VERSION 5.8 ;
BUSBITCHARS "[]" ;
DIVIDERCHAR "/" ;
UNITS
    DATABASE MICRONS 1000 ;
END UNITS

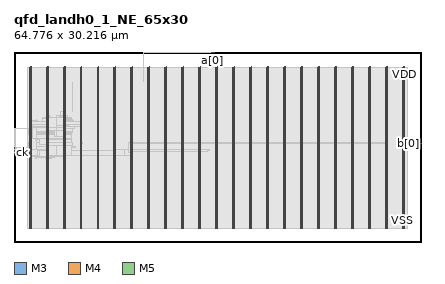
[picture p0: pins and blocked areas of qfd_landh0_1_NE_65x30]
MACRO qfd_landh0_1_NE_65x30
  FOREIGN qfd_landh0_1_NE_65x30 0 0 ;
  CLASS BLOCK ;
  SIZE 64.776 BY 30.216 ;
  PIN a[0]
    DIRECTION INPUT ;
    USE SIGNAL ;
    PORT
      LAYER M3 ;
        RECT  31.86 30.179 31.878 30.216 ;
    END
    PORT
      LAYER M3 ;
        RECT  31.356 30.109 31.878 30.204 ;
    END
  END a[0]
  PIN b[0]
    DIRECTION OUTPUT ;
    USE SIGNAL ;
    PORT
      LAYER M4 ;
        RECT  64.692 15.6 64.776 15.624 ;
    END
    PORT
      LAYER M4 ;
        RECT  63.853 15.6 64.716 15.624 ;
    END
  END b[0]
  PIN ck
    DIRECTION INPUT ;
    USE SIGNAL ;
    PORT
      LAYER M4 ;
        RECT  0 14.16 0.084 14.184 ;
    END
  END ck
  PIN ck_s
    DIRECTION INPUT ;
    USE SIGNAL ;
    PORT
      LAYER M4 ;
        RECT  0 14.256 0.084 14.28 ;
    END
  END ck_s
  PIN en
    DIRECTION INPUT ;
    USE SIGNAL ;
    PORT
      LAYER M4 ;
        RECT  0 14.352 0.084 14.376 ;
    END
  END en
  PIN fault
    DIRECTION OUTPUT ;
    USE SIGNAL ;
    PORT
      LAYER M4 ;
        RECT  0 14.448 0.084 14.472 ;
    END
  END fault
  PIN k0
    DIRECTION INPUT ;
    USE SIGNAL ;
    PORT
      LAYER M4 ;
        RECT  0 14.544 0.084 14.568 ;
    END
  END k0
  PIN k1
    DIRECTION INPUT ;
    USE SIGNAL ;
    PORT
      LAYER M4 ;
        RECT  0 14.64 0.084 14.664 ;
    END
  END k1
  PIN k2
    DIRECTION INPUT ;
    USE SIGNAL ;
    PORT
      LAYER M4 ;
        RECT  0 14.736 0.084 14.76 ;
    END
  END k2
  PIN rs
    DIRECTION INPUT ;
    USE SIGNAL ;
    PORT
      LAYER M4 ;
        RECT  0 14.832 0.084 14.856 ;
    END
  END rs
  PIN tie_hi
    DIRECTION OUTPUT ;
    USE SIGNAL ;
    PORT
      LAYER M4 ;
        RECT  0 14.928 0.084 14.952 ;
    END
  END tie_hi
  PIN tie_lo
    DIRECTION OUTPUT ;
    USE SIGNAL ;
    PORT
      LAYER M4 ;
        RECT  0 15.024 0.084 15.048 ;
    END
  END tie_lo
  PIN VDD
    DIRECTION INOUT ;
    USE POWER ;
    PORT
      LAYER M5 ;
        RECT  61.992 2.151 62.112 27.833 ;
        RECT  59.292 2.151 59.412 27.833 ;
        RECT  56.592 2.151 56.712 27.833 ;
        RECT  53.892 2.151 54.012 27.833 ;
        RECT  51.192 2.151 51.312 27.833 ;
        RECT  48.492 2.151 48.612 27.833 ;
        RECT  45.792 2.151 45.912 27.833 ;
        RECT  43.092 2.151 43.212 27.833 ;
        RECT  40.392 2.151 40.512 27.833 ;
        RECT  37.692 2.151 37.812 27.833 ;
        RECT  34.992 2.151 35.112 27.833 ;
        RECT  32.292 2.151 32.412 27.833 ;
        RECT  29.592 2.151 29.712 27.833 ;
        RECT  26.892 2.151 27.012 27.833 ;
        RECT  24.192 2.151 24.312 27.833 ;
        RECT  21.492 2.151 21.612 27.833 ;
        RECT  18.792 2.151 18.912 27.833 ;
        RECT  16.092 2.151 16.212 27.833 ;
        RECT  13.392 2.151 13.512 27.833 ;
        RECT  10.692 2.151 10.812 27.833 ;
        RECT  7.992 2.151 8.112 27.833 ;
        RECT  5.292 2.151 5.412 27.833 ;
        RECT  2.592 2.151 2.712 27.833 ;
    END
  END VDD
  PIN VSS
    DIRECTION INOUT ;
    USE GROUND ;
    PORT
      LAYER M5 ;
        RECT  61.8 2.137 61.92 27.819 ;
        RECT  59.1 2.137 59.22 27.819 ;
        RECT  56.4 2.137 56.52 27.819 ;
        RECT  53.7 2.137 53.82 27.819 ;
        RECT  51 2.137 51.12 27.819 ;
        RECT  48.3 2.137 48.42 27.819 ;
        RECT  45.6 2.137 45.72 27.819 ;
        RECT  42.9 2.137 43.02 27.819 ;
        RECT  40.2 2.137 40.32 27.819 ;
        RECT  37.5 2.137 37.62 27.819 ;
        RECT  34.8 2.137 34.92 27.819 ;
        RECT  32.1 2.137 32.22 27.819 ;
        RECT  29.4 2.137 29.52 27.819 ;
        RECT  26.7 2.137 26.82 27.819 ;
        RECT  24 2.137 24.12 27.819 ;
        RECT  21.3 2.137 21.42 27.819 ;
        RECT  18.6 2.137 18.72 27.819 ;
        RECT  15.9 2.137 16.02 27.819 ;
        RECT  13.2 2.137 13.32 27.819 ;
        RECT  10.5 2.137 10.62 27.819 ;
        RECT  7.8 2.137 7.92 27.819 ;
        RECT  5.1 2.137 5.22 27.819 ;
        RECT  2.4 2.137 2.52 27.819 ;
    END
  END VSS
  # OT_OBS_CLOSED layer=M5 d_um=1.536 added=3
  OBS
    LAYER RVTN ;
     RECT  2.16 2.16 62.586 2.295 ;
     RECT  2.16 2.565 62.586 2.835 ;
     RECT  2.16 3.105 62.586 3.375 ;
     RECT  2.16 3.645 62.586 3.915 ;
     RECT  2.16 4.185 62.586 4.455 ;
     RECT  2.16 4.725 62.586 4.995 ;
     RECT  2.16 5.265 62.586 5.535 ;
     RECT  2.16 5.805 62.586 6.075 ;
     RECT  2.16 6.345 62.586 6.615 ;
     RECT  2.16 6.885 62.586 7.155 ;
     RECT  2.16 7.425 62.586 7.695 ;
     RECT  2.16 7.965 62.586 8.235 ;
     RECT  2.16 8.505 62.586 8.775 ;
     RECT  2.16 9.045 62.586 9.315 ;
     RECT  2.16 9.585 62.586 9.855 ;
     RECT  2.16 10.125 62.586 10.395 ;
     RECT  2.16 10.665 62.586 10.935 ;
     RECT  2.16 11.205 62.586 11.475 ;
     RECT  2.16 11.745 62.586 12.015 ;
     RECT  2.16 12.285 62.586 12.555 ;
     RECT  2.16 12.825 62.586 13.095 ;
     RECT  2.16 13.365 62.586 13.635 ;
     RECT  2.16 13.905 62.586 14.175 ;
     RECT  2.16 14.445 62.586 14.715 ;
     RECT  2.16 14.985 62.586 15.255 ;
     RECT  2.16 15.525 62.586 15.795 ;
     RECT  2.16 16.065 62.586 16.335 ;
     RECT  2.16 16.605 62.586 16.875 ;
     RECT  2.16 17.145 62.586 17.415 ;
     RECT  2.16 17.685 62.586 17.955 ;
     RECT  2.16 18.225 62.586 18.495 ;
     RECT  2.16 18.765 62.586 19.035 ;
     RECT  2.16 19.305 62.586 19.575 ;
     RECT  2.16 19.845 62.586 20.115 ;
     RECT  2.16 20.385 62.586 20.655 ;
     RECT  2.16 20.925 62.586 21.195 ;
     RECT  2.16 21.465 62.586 21.735 ;
     RECT  2.16 22.005 62.586 22.275 ;
     RECT  2.16 22.545 62.586 22.815 ;
     RECT  2.16 23.085 62.586 23.355 ;
     RECT  2.16 23.625 62.586 23.895 ;
     RECT  2.16 24.165 62.586 24.435 ;
     RECT  2.16 24.705 62.586 24.975 ;
     RECT  2.16 25.245 62.586 25.515 ;
     RECT  2.16 25.785 62.586 26.055 ;
     RECT  2.16 26.325 62.586 26.595 ;
     RECT  2.16 26.865 62.586 27.135 ;
     RECT  2.16 27.405 62.586 27.675 ;
    LAYER RVTP ;
     RECT  2.16 2.295 62.586 2.565 ;
     RECT  2.16 2.835 62.586 3.105 ;
     RECT  2.16 3.375 62.586 3.645 ;
     RECT  2.16 3.915 62.586 4.185 ;
     RECT  2.16 4.455 62.586 4.725 ;
     RECT  2.16 4.995 62.586 5.265 ;
     RECT  2.16 5.535 62.586 5.805 ;
     RECT  2.16 6.075 62.586 6.345 ;
     RECT  2.16 6.615 62.586 6.885 ;
     RECT  2.16 7.155 62.586 7.425 ;
     RECT  2.16 7.695 62.586 7.965 ;
     RECT  2.16 8.235 62.586 8.505 ;
     RECT  2.16 8.775 62.586 9.045 ;
     RECT  2.16 9.315 62.586 9.585 ;
     RECT  2.16 9.855 62.586 10.125 ;
     RECT  2.16 10.395 62.586 10.665 ;
     RECT  2.16 10.935 62.586 11.205 ;
     RECT  2.16 11.475 62.586 11.745 ;
     RECT  2.16 12.015 62.586 12.285 ;
     RECT  2.16 12.555 62.586 12.825 ;
     RECT  2.16 13.095 62.586 13.365 ;
     RECT  2.16 13.635 62.586 13.905 ;
     RECT  2.16 14.175 62.586 14.445 ;
     RECT  2.16 14.715 62.586 14.985 ;
     RECT  2.16 15.255 62.586 15.525 ;
     RECT  2.16 15.795 62.586 16.065 ;
     RECT  2.16 16.335 62.586 16.605 ;
     RECT  2.16 16.875 62.586 17.145 ;
     RECT  2.16 17.415 62.586 17.685 ;
     RECT  2.16 17.955 62.586 18.225 ;
     RECT  2.16 18.495 62.586 18.765 ;
     RECT  2.16 19.035 62.586 19.305 ;
     RECT  2.16 19.575 62.586 19.845 ;
     RECT  2.16 20.115 62.586 20.385 ;
     RECT  2.16 20.655 62.586 20.925 ;
     RECT  2.16 21.195 62.586 21.465 ;
     RECT  2.16 21.735 62.586 22.005 ;
     RECT  2.16 22.275 62.586 22.545 ;
     RECT  2.16 22.815 62.586 23.085 ;
     RECT  2.16 23.355 62.586 23.625 ;
     RECT  2.16 23.895 62.586 24.165 ;
     RECT  2.16 24.435 62.586 24.705 ;
     RECT  2.16 24.975 62.586 25.245 ;
     RECT  2.16 25.515 62.586 25.785 ;
     RECT  2.16 26.055 62.586 26.325 ;
     RECT  2.16 26.595 62.586 26.865 ;
     RECT  2.16 27.135 62.586 27.405 ;
     RECT  2.16 27.675 62.586 27.81 ;
    LAYER M1 ;
     RECT  2.16 2.151 62.586 27.819 ;
    LAYER M2 ;
     RECT  0.103 14.454 0.455 14.742 ;
     RECT  20.551 30.186 31.351 30.204 ;
     RECT  31.351 30.114 31.379 30.204 ;
     RECT  31.379 30.114 31.883 30.132 ;
     RECT  2.16 2.151 62.586 27.819 ;
     RECT  62.586 15.732 63.887 15.75 ;
    LAYER M3 ;
     RECT  2.415 2.143 2.505 2.413 ;
     RECT  5.115 2.143 5.205 2.413 ;
     RECT  7.815 2.143 7.905 2.413 ;
     RECT  10.515 2.143 10.605 2.413 ;
     RECT  13.215 2.143 13.305 2.413 ;
     RECT  15.915 2.143 16.005 2.413 ;
     RECT  18.615 2.143 18.705 2.413 ;
     RECT  21.315 2.143 21.405 2.413 ;
     RECT  24.015 2.143 24.105 2.413 ;
     RECT  26.715 2.143 26.805 2.413 ;
     RECT  29.415 2.143 29.505 2.413 ;
     RECT  32.115 2.143 32.205 2.413 ;
     RECT  34.815 2.143 34.905 2.413 ;
     RECT  37.515 2.143 37.605 2.413 ;
     RECT  40.215 2.143 40.305 2.413 ;
     RECT  42.915 2.143 43.005 2.413 ;
     RECT  45.615 2.143 45.705 2.413 ;
     RECT  48.315 2.143 48.405 2.413 ;
     RECT  51.015 2.143 51.105 2.413 ;
     RECT  53.715 2.143 53.805 2.413 ;
     RECT  56.415 2.143 56.505 2.413 ;
     RECT  59.115 2.143 59.205 2.413 ;
     RECT  61.815 2.143 61.905 2.413 ;
     RECT  5.115 2.413 5.397 13.297 ;
     RECT  5.115 13.297 5.922 13.333 ;
     RECT  4.32 13.333 4.338 13.369 ;
     RECT  5.076 13.333 6.03 13.369 ;
     RECT  3.492 13.261 3.51 13.405 ;
     RECT  4.32 13.369 6.03 13.405 ;
     RECT  3.492 13.405 6.03 13.441 ;
     RECT  2.415 2.413 2.697 13.531 ;
     RECT  3.492 13.441 6.426 13.531 ;
     RECT  7.815 2.413 8.097 13.531 ;
     RECT  2.415 13.531 6.426 13.667 ;
     RECT  6.228 13.667 6.426 13.675 ;
     RECT  7.236 13.531 8.097 13.675 ;
     RECT  18.615 2.413 18.897 13.819 ;
     RECT  2.415 13.667 5.49 14.143 ;
     RECT  18 13.819 18.897 14.215 ;
     RECT  17.532 14.215 18.897 14.237 ;
     RECT  2.376 14.143 5.49 14.347 ;
     RECT  15.915 2.413 16.197 14.347 ;
     RECT  0.144 14.299 0.162 14.44 ;
     RECT  0.108 14.44 0.162 14.449 ;
     RECT  30.744 14.443 30.762 14.611 ;
     RECT  17.532 14.237 17.658 14.635 ;
     RECT  30.744 14.611 31.086 14.639 ;
     RECT  15.876 14.347 16.197 14.669 ;
     RECT  2.304 14.347 5.49 14.675 ;
     RECT  17.424 14.635 17.658 14.675 ;
     RECT  17.532 14.675 17.55 14.717 ;
     RECT  31.068 14.639 31.086 14.717 ;
     RECT  0.108 14.449 0.45 14.747 ;
     RECT  0.144 14.747 0.45 14.765 ;
     RECT  2.304 14.675 2.826 14.765 ;
     RECT  6.228 13.675 8.097 15.061 ;
     RECT  9.036 15.025 9.702 15.061 ;
     RECT  6.228 15.061 9.702 15.179 ;
     RECT  3.636 14.675 5.49 15.259 ;
     RECT  6.228 15.179 9.27 15.259 ;
     RECT  10.515 2.413 10.797 15.691 ;
     RECT  59.115 2.413 59.397 15.727 ;
     RECT  61.815 2.413 62.097 15.727 ;
     RECT  2.304 14.765 2.697 15.755 ;
     RECT  3.636 15.259 9.27 15.755 ;
     RECT  63.864 15.595 63.882 15.755 ;
     RECT  59.112 15.727 59.397 15.773 ;
     RECT  10.515 15.691 10.854 15.899 ;
     RECT  61.56 15.727 62.097 15.899 ;
     RECT  3.636 15.755 9.162 16.339 ;
     RECT  3.456 16.339 9.162 16.411 ;
     RECT  2.415 15.755 2.697 16.459 ;
     RECT  3.42 16.411 9.162 16.459 ;
     RECT  2.415 16.459 9.162 17.083 ;
     RECT  2.376 17.083 9.162 17.221 ;
     RECT  2.376 17.221 9.198 17.491 ;
     RECT  2.376 17.491 9.234 17.609 ;
     RECT  2.415 17.609 9.234 18.031 ;
     RECT  2.415 18.031 9.594 18.301 ;
     RECT  10.515 15.899 10.797 18.301 ;
     RECT  2.415 18.301 10.797 18.689 ;
     RECT  2.415 18.689 5.397 19.229 ;
     RECT  6.12 18.689 10.797 19.229 ;
     RECT  6.12 19.229 9.522 19.265 ;
     RECT  2.415 19.229 3.726 19.301 ;
     RECT  3.528 19.301 3.726 19.373 ;
     RECT  6.12 19.265 9.306 19.499 ;
     RECT  3.528 19.373 3.546 19.535 ;
     RECT  4.5 19.229 5.397 19.579 ;
     RECT  6.12 19.499 9.162 19.579 ;
     RECT  4.5 19.579 9.162 19.769 ;
     RECT  4.644 19.769 8.586 19.841 ;
     RECT  5.115 19.841 8.586 19.877 ;
     RECT  5.115 19.877 5.85 19.949 ;
     RECT  6.732 19.877 8.586 20.039 ;
     RECT  5.115 19.949 5.67 20.075 ;
     RECT  6.732 20.039 8.406 20.075 ;
     RECT  7.38 20.075 8.19 20.687 ;
     RECT  9.252 20.695 9.27 25.439 ;
     RECT  2.415 19.301 2.697 27.557 ;
     RECT  5.115 20.075 5.397 27.557 ;
     RECT  7.815 20.687 8.097 27.557 ;
     RECT  10.515 19.229 10.797 27.557 ;
     RECT  13.215 2.413 13.497 27.557 ;
     RECT  15.915 14.669 16.197 27.557 ;
     RECT  18.615 14.237 18.897 27.557 ;
     RECT  21.315 2.413 21.597 27.557 ;
     RECT  24.015 2.413 24.297 27.557 ;
     RECT  26.715 2.413 26.997 27.557 ;
     RECT  29.415 2.413 29.697 27.557 ;
     RECT  32.115 2.413 32.397 27.557 ;
     RECT  34.815 2.413 35.097 27.557 ;
     RECT  37.515 2.413 37.797 27.557 ;
     RECT  40.215 2.413 40.497 27.557 ;
     RECT  42.915 2.413 43.197 27.557 ;
     RECT  45.615 2.413 45.897 27.557 ;
     RECT  48.315 2.413 48.597 27.557 ;
     RECT  51.015 2.413 51.297 27.557 ;
     RECT  53.715 2.413 53.997 27.557 ;
     RECT  56.415 2.413 56.697 27.557 ;
     RECT  59.115 15.773 59.397 27.557 ;
     RECT  61.815 15.899 62.097 27.557 ;
     RECT  2.607 27.557 2.697 27.827 ;
     RECT  5.307 27.557 5.397 27.827 ;
     RECT  8.007 27.557 8.097 27.827 ;
     RECT  10.707 27.557 10.797 27.827 ;
     RECT  13.407 27.557 13.497 27.827 ;
     RECT  16.107 27.557 16.197 27.827 ;
     RECT  18.807 27.557 18.897 27.827 ;
     RECT  21.507 27.557 21.597 27.827 ;
     RECT  24.207 27.557 24.297 27.827 ;
     RECT  26.907 27.557 26.997 27.827 ;
     RECT  29.607 27.557 29.697 27.827 ;
     RECT  32.307 27.557 32.397 27.827 ;
     RECT  35.007 27.557 35.097 27.827 ;
     RECT  37.707 27.557 37.797 27.827 ;
     RECT  40.407 27.557 40.497 27.827 ;
     RECT  43.107 27.557 43.197 27.827 ;
     RECT  45.807 27.557 45.897 27.827 ;
     RECT  48.507 27.557 48.597 27.827 ;
     RECT  51.207 27.557 51.297 27.827 ;
     RECT  53.907 27.557 53.997 27.827 ;
     RECT  56.607 27.557 56.697 27.827 ;
     RECT  59.307 27.557 59.397 27.827 ;
     RECT  62.007 27.557 62.097 27.827 ;
     RECT  20.556 25.555 20.574 30.209 ;
     RECT  31.356 30.204 31.374 30.209 ;
    LAYER M4 ;
     RECT  0.084 14.16 0.371 14.184 ;
     RECT  0.06 14.184 0.371 14.256 ;
     RECT  0.084 14.256 0.371 14.28 ;
     RECT  0.06 14.28 0.371 14.352 ;
     RECT  0.084 14.352 0.371 14.376 ;
     RECT  0.06 14.376 0.371 14.448 ;
     RECT  0.084 14.448 0.371 14.472 ;
     RECT  0.06 14.472 0.371 14.544 ;
     RECT  0.084 14.544 0.371 14.568 ;
     RECT  0.06 14.568 0.371 14.64 ;
     RECT  0.084 14.64 0.371 14.664 ;
     RECT  0.06 14.664 0.371 14.736 ;
     RECT  0.084 14.736 0.371 14.76 ;
     RECT  0.06 14.76 0.371 14.832 ;
     RECT  0.084 14.832 0.371 14.856 ;
     RECT  0.06 14.856 0.371 14.928 ;
     RECT  0.084 14.928 0.371 14.952 ;
     RECT  0.06 14.952 0.371 15.024 ;
     RECT  0.084 15.024 0.371 15.048 ;
     RECT  0.133 18 2.365 18.024 ;
     RECT  0.371 14.304 2.408 15.048 ;
     RECT  2.365 17.088 2.408 18.024 ;
     RECT  2.408 2.148 2.512 27.552 ;
     RECT  2.512 2.418 2.6 27.552 ;
     RECT  2.6 2.418 2.704 27.822 ;
     RECT  2.704 13.824 2.837 14.76 ;
     RECT  2.704 16.464 2.945 18.456 ;
     RECT  2.945 16.464 3.593 18.264 ;
     RECT  2.837 13.824 3.665 14.712 ;
     RECT  3.665 13.824 4.057 14.472 ;
     RECT  3.593 16.464 4.093 16.488 ;
     RECT  4.057 13.632 5.108 14.472 ;
     RECT  4.093 15.552 5.108 16.488 ;
     RECT  3.593 17.616 5.108 18.264 ;
     RECT  5.108 2.148 5.212 27.552 ;
     RECT  5.212 2.418 5.3 27.552 ;
     RECT  5.3 2.418 5.404 27.822 ;
     RECT  5.404 13.68 5.537 15.576 ;
     RECT  5.404 17.616 6.469 18.264 ;
     RECT  5.537 13.68 6.689 15.288 ;
     RECT  6.469 16.704 6.785 18.264 ;
     RECT  6.709 19.776 6.796 19.8 ;
     RECT  6.689 13.824 7.808 15.288 ;
     RECT  6.785 16.704 7.808 18.456 ;
     RECT  7.297 19.92 7.808 19.944 ;
     RECT  7.808 2.148 7.912 27.552 ;
     RECT  7.912 2.418 8 27.552 ;
     RECT  8 2.418 8.104 27.822 ;
     RECT  8.104 18.432 8.741 18.456 ;
     RECT  8.104 13.824 9.173 15.288 ;
     RECT  9.173 13.824 10.508 14.472 ;
     RECT  10.508 2.148 10.612 27.552 ;
     RECT  10.612 2.418 10.7 27.552 ;
     RECT  10.7 2.418 10.804 27.822 ;
     RECT  10.804 13.824 13.208 14.472 ;
     RECT  13.208 2.148 13.312 27.552 ;
     RECT  13.312 2.418 13.4 27.552 ;
     RECT  13.4 2.418 13.504 27.822 ;
     RECT  13.504 13.824 15.865 14.472 ;
     RECT  15.865 13.824 15.908 14.664 ;
     RECT  15.908 2.148 16.012 27.552 ;
     RECT  16.012 2.418 16.1 27.552 ;
     RECT  16.1 2.418 16.204 27.822 ;
     RECT  16.204 13.824 17.521 14.664 ;
     RECT  17.521 13.824 18.608 14.712 ;
     RECT  18.181 15.744 18.608 15.768 ;
     RECT  18.608 2.148 18.712 27.552 ;
     RECT  18.712 2.418 18.8 27.552 ;
     RECT  18.8 2.418 18.904 27.822 ;
     RECT  18.904 14.448 21.308 14.712 ;
     RECT  18.904 15.744 21.308 15.768 ;
     RECT  21.308 2.148 21.412 27.552 ;
     RECT  21.412 2.418 21.5 27.552 ;
     RECT  21.5 2.418 21.604 27.822 ;
     RECT  21.604 14.448 24.008 14.712 ;
     RECT  21.604 15.744 24.008 15.768 ;
     RECT  24.008 2.148 24.112 27.552 ;
     RECT  24.112 2.418 24.2 27.552 ;
     RECT  24.2 2.418 24.304 27.822 ;
     RECT  24.304 14.448 26.708 14.712 ;
     RECT  24.304 15.744 26.708 15.768 ;
     RECT  26.708 2.148 26.812 27.552 ;
     RECT  26.812 2.418 26.9 27.552 ;
     RECT  26.9 2.418 27.004 27.822 ;
     RECT  27.004 14.448 29.408 14.712 ;
     RECT  27.004 15.744 29.408 15.768 ;
     RECT  29.408 2.148 29.512 27.552 ;
     RECT  29.512 2.418 29.6 27.552 ;
     RECT  29.6 2.418 29.704 27.822 ;
     RECT  29.704 14.448 30.773 14.712 ;
     RECT  30.773 14.688 31.097 14.712 ;
     RECT  29.704 15.744 32.108 15.768 ;
     RECT  32.108 2.148 32.212 27.552 ;
     RECT  32.212 2.418 32.3 27.552 ;
     RECT  32.3 2.418 32.404 27.822 ;
     RECT  32.404 15.744 34.808 15.768 ;
     RECT  34.808 2.148 34.912 27.552 ;
     RECT  34.912 2.418 35 27.552 ;
     RECT  35 2.418 35.104 27.822 ;
     RECT  35.104 15.744 37.508 15.768 ;
     RECT  37.508 2.148 37.612 27.552 ;
     RECT  37.612 2.418 37.7 27.552 ;
     RECT  37.7 2.418 37.804 27.822 ;
     RECT  37.804 15.744 40.208 15.768 ;
     RECT  40.208 2.148 40.312 27.552 ;
     RECT  40.312 2.418 40.4 27.552 ;
     RECT  40.4 2.418 40.504 27.822 ;
     RECT  40.504 15.744 42.908 15.768 ;
     RECT  42.908 2.148 43.012 27.552 ;
     RECT  43.012 2.418 43.1 27.552 ;
     RECT  43.1 2.418 43.204 27.822 ;
     RECT  43.204 15.744 45.608 15.768 ;
     RECT  45.608 2.148 45.712 27.552 ;
     RECT  45.712 2.418 45.8 27.552 ;
     RECT  45.8 2.418 45.904 27.822 ;
     RECT  45.904 15.744 48.308 15.768 ;
     RECT  48.308 2.148 48.412 27.552 ;
     RECT  48.412 2.418 48.5 27.552 ;
     RECT  48.5 2.418 48.604 27.822 ;
     RECT  48.604 15.744 51.008 15.768 ;
     RECT  51.008 2.148 51.112 27.552 ;
     RECT  51.112 2.418 51.2 27.552 ;
     RECT  51.2 2.418 51.304 27.822 ;
     RECT  51.304 15.744 53.708 15.768 ;
     RECT  53.708 2.148 53.812 27.552 ;
     RECT  53.812 2.418 53.9 27.552 ;
     RECT  53.9 2.418 54.004 27.822 ;
     RECT  54.004 15.744 56.408 15.768 ;
     RECT  56.408 2.148 56.512 27.552 ;
     RECT  56.512 2.418 56.6 27.552 ;
     RECT  56.6 2.418 56.704 27.822 ;
     RECT  56.704 15.744 59.108 15.768 ;
     RECT  59.108 2.148 59.212 27.552 ;
     RECT  59.212 2.418 59.3 27.552 ;
     RECT  59.3 2.418 59.404 27.822 ;
     RECT  61.808 2.148 61.912 27.552 ;
     RECT  61.912 2.418 62 27.552 ;
     RECT  62 2.418 62.104 27.822 ;
    LAYER M5 ;
     RECT  2.4 2.137 2.52 2.151 ;
     RECT  5.1 2.137 5.22 2.151 ;
     RECT  7.8 2.137 7.92 2.151 ;
     RECT  10.5 2.137 10.62 2.151 ;
     RECT  13.2 2.137 13.32 2.151 ;
     RECT  15.9 2.137 16.02 2.151 ;
     RECT  18.6 2.137 18.72 2.151 ;
     RECT  21.3 2.137 21.42 2.151 ;
     RECT  24 2.137 24.12 2.151 ;
     RECT  26.7 2.137 26.82 2.151 ;
     RECT  29.4 2.137 29.52 2.151 ;
     RECT  32.1 2.137 32.22 2.151 ;
     RECT  34.8 2.137 34.92 2.151 ;
     RECT  37.5 2.137 37.62 2.151 ;
     RECT  40.2 2.137 40.32 2.151 ;
     RECT  42.9 2.137 43.02 2.151 ;
     RECT  45.6 2.137 45.72 2.151 ;
     RECT  48.3 2.137 48.42 2.151 ;
     RECT  51 2.137 51.12 2.151 ;
     RECT  53.7 2.137 53.82 2.151 ;
     RECT  56.4 2.137 56.52 2.151 ;
     RECT  59.1 2.137 59.22 2.151 ;
     RECT  61.8 2.137 61.92 2.151 ;
     RECT  18.6 2.151 18.912 14.197 ;
     RECT  0.336 14.149 0.36 14.245 ;
     RECT  0.144 14.245 0.36 14.483 ;
     RECT  18.192 14.197 18.912 15.779 ;
     RECT  2.4 2.151 2.712 17.077 ;
     RECT  7.8 2.151 8.112 17.701 ;
     RECT  2.4 17.077 2.952 17.843 ;
     RECT  0.144 14.483 0.168 18.035 ;
     RECT  6.816 17.701 8.112 18.229 ;
     RECT  6.72 18.229 8.112 18.467 ;
     RECT  6.72 18.467 6.744 19.811 ;
     RECT  2.4 17.843 2.712 27.819 ;
     RECT  5.1 2.151 5.412 27.819 ;
     RECT  7.8 18.467 8.112 27.819 ;
     RECT  10.5 2.151 10.812 27.819 ;
     RECT  13.2 2.151 13.512 27.819 ;
     RECT  15.9 2.151 16.212 27.819 ;
     RECT  18.6 15.779 18.912 27.819 ;
     RECT  21.3 2.151 21.612 27.819 ;
     RECT  24 2.151 24.312 27.819 ;
     RECT  26.7 2.151 27.012 27.819 ;
     RECT  29.4 2.151 29.712 27.819 ;
     RECT  32.1 2.151 32.412 27.819 ;
     RECT  34.8 2.151 35.112 27.819 ;
     RECT  37.5 2.151 37.812 27.819 ;
     RECT  40.2 2.151 40.512 27.819 ;
     RECT  42.9 2.151 43.212 27.819 ;
     RECT  45.6 2.151 45.912 27.819 ;
     RECT  48.3 2.151 48.612 27.819 ;
     RECT  51 2.151 51.312 27.819 ;
     RECT  53.7 2.151 54.012 27.819 ;
     RECT  56.4 2.151 56.712 27.819 ;
     RECT  59.1 2.151 59.412 27.819 ;
     RECT  61.8 2.151 62.112 27.819 ;
     RECT  2.592 27.819 2.712 27.833 ;
     RECT  5.292 27.819 5.412 27.833 ;
     RECT  7.992 27.819 8.112 27.833 ;
     RECT  10.692 27.819 10.812 27.833 ;
     RECT  13.392 27.819 13.512 27.833 ;
     RECT  16.092 27.819 16.212 27.833 ;
     RECT  18.792 27.819 18.912 27.833 ;
     RECT  21.492 27.819 21.612 27.833 ;
     RECT  24.192 27.819 24.312 27.833 ;
     RECT  26.892 27.819 27.012 27.833 ;
     RECT  29.592 27.819 29.712 27.833 ;
     RECT  32.292 27.819 32.412 27.833 ;
     RECT  34.992 27.819 35.112 27.833 ;
     RECT  37.692 27.819 37.812 27.833 ;
     RECT  40.392 27.819 40.512 27.833 ;
     RECT  43.092 27.819 43.212 27.833 ;
     RECT  45.792 27.819 45.912 27.833 ;
     RECT  48.492 27.819 48.612 27.833 ;
     RECT  51.192 27.819 51.312 27.833 ;
     RECT  53.892 27.819 54.012 27.833 ;
     RECT  56.592 27.819 56.712 27.833 ;
     RECT  59.292 27.819 59.412 27.833 ;
     RECT  61.992 27.819 62.112 27.833 ;
     RECT  5.412 17.701 6.816 18.229 ;
     RECT  5.412 18.229 6.72 19.811 ;
     RECT  6.744 18.467 7.8 19.811 ;
  END
END qfd_landh0_1_NE_65x30
END LIBRARY
